VERSION 5.4 ;
NAMESCASESENSITIVE ON ;
BUSBITCHARS "[]" ;
DIVIDERCHAR "/" ;
UNITS
  DATABASE MICRONS 2000 ;
END UNITS
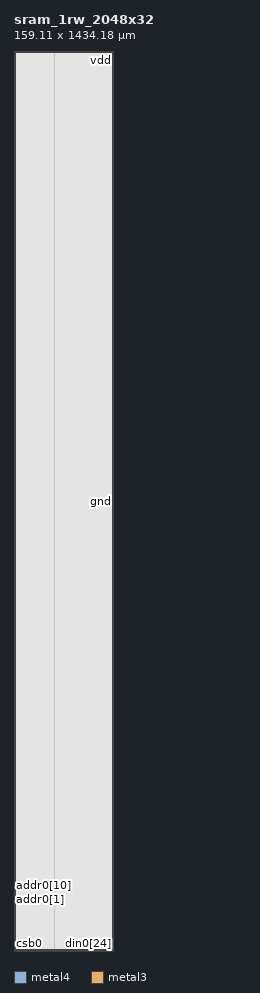
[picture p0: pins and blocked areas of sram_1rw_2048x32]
MACRO sram_1rw_2048x32
   CLASS BLOCK ;
   SIZE 159.11 BY 1434.18 ;
   SYMMETRY X Y R90 ;
   PIN din0[0]
      DIRECTION INPUT ;
      PORT
         LAYER metal4 ;
         RECT  64.725 0.0 64.865 0.14 ;
      END
   END din0[0]
   PIN din0[1]
      DIRECTION INPUT ;
      PORT
         LAYER metal4 ;
         RECT  67.585 0.0 67.725 0.14 ;
      END
   END din0[1]
   PIN din0[2]
      DIRECTION INPUT ;
      PORT
         LAYER metal4 ;
         RECT  70.445 0.0 70.585 0.14 ;
      END
   END din0[2]
   PIN din0[3]
      DIRECTION INPUT ;
      PORT
         LAYER metal4 ;
         RECT  73.305 0.0 73.445 0.14 ;
      END
   END din0[3]
   PIN din0[4]
      DIRECTION INPUT ;
      PORT
         LAYER metal4 ;
         RECT  76.165 0.0 76.305 0.14 ;
      END
   END din0[4]
   PIN din0[5]
      DIRECTION INPUT ;
      PORT
         LAYER metal4 ;
         RECT  79.025 0.0 79.165 0.14 ;
      END
   END din0[5]
   PIN din0[6]
      DIRECTION INPUT ;
      PORT
         LAYER metal4 ;
         RECT  81.885 0.0 82.025 0.14 ;
      END
   END din0[6]
   PIN din0[7]
      DIRECTION INPUT ;
      PORT
         LAYER metal4 ;
         RECT  84.745 0.0 84.885 0.14 ;
      END
   END din0[7]
   PIN din0[8]
      DIRECTION INPUT ;
      PORT
         LAYER metal4 ;
         RECT  87.605 0.0 87.745 0.14 ;
      END
   END din0[8]
   PIN din0[9]
      DIRECTION INPUT ;
      PORT
         LAYER metal4 ;
         RECT  90.465 0.0 90.605 0.14 ;
      END
   END din0[9]
   PIN din0[10]
      DIRECTION INPUT ;
      PORT
         LAYER metal4 ;
         RECT  93.325 0.0 93.465 0.14 ;
      END
   END din0[10]
   PIN din0[11]
      DIRECTION INPUT ;
      PORT
         LAYER metal4 ;
         RECT  96.185 0.0 96.325 0.14 ;
      END
   END din0[11]
   PIN din0[12]
      DIRECTION INPUT ;
      PORT
         LAYER metal4 ;
         RECT  99.045 0.0 99.185 0.14 ;
      END
   END din0[12]
   PIN din0[13]
      DIRECTION INPUT ;
      PORT
         LAYER metal4 ;
         RECT  101.905 0.0 102.045 0.14 ;
      END
   END din0[13]
   PIN din0[14]
      DIRECTION INPUT ;
      PORT
         LAYER metal4 ;
         RECT  104.765 0.0 104.905 0.14 ;
      END
   END din0[14]
   PIN din0[15]
      DIRECTION INPUT ;
      PORT
         LAYER metal4 ;
         RECT  107.625 0.0 107.765 0.14 ;
      END
   END din0[15]
   PIN din0[16]
      DIRECTION INPUT ;
      PORT
         LAYER metal4 ;
         RECT  110.485 0.0 110.625 0.14 ;
      END
   END din0[16]
   PIN din0[17]
      DIRECTION INPUT ;
      PORT
         LAYER metal4 ;
         RECT  113.345 0.0 113.485 0.14 ;
      END
   END din0[17]
   PIN din0[18]
      DIRECTION INPUT ;
      PORT
         LAYER metal4 ;
         RECT  116.205 0.0 116.345 0.14 ;
      END
   END din0[18]
   PIN din0[19]
      DIRECTION INPUT ;
      PORT
         LAYER metal4 ;
         RECT  119.065 0.0 119.205 0.14 ;
      END
   END din0[19]
   PIN din0[20]
      DIRECTION INPUT ;
      PORT
         LAYER metal4 ;
         RECT  121.925 0.0 122.065 0.14 ;
      END
   END din0[20]
   PIN din0[21]
      DIRECTION INPUT ;
      PORT
         LAYER metal4 ;
         RECT  124.785 0.0 124.925 0.14 ;
      END
   END din0[21]
   PIN din0[22]
      DIRECTION INPUT ;
      PORT
         LAYER metal4 ;
         RECT  127.645 0.0 127.785 0.14 ;
      END
   END din0[22]
   PIN din0[23]
      DIRECTION INPUT ;
      PORT
         LAYER metal4 ;
         RECT  130.505 0.0 130.645 0.14 ;
      END
   END din0[23]
   PIN din0[24]
      DIRECTION INPUT ;
      PORT
         LAYER metal4 ;
         RECT  133.365 0.0 133.505 0.14 ;
      END
   END din0[24]
   PIN din0[25]
      DIRECTION INPUT ;
      PORT
         LAYER metal4 ;
         RECT  136.225 0.0 136.365 0.14 ;
      END
   END din0[25]
   PIN din0[26]
      DIRECTION INPUT ;
      PORT
         LAYER metal4 ;
         RECT  139.085 0.0 139.225 0.14 ;
      END
   END din0[26]
   PIN din0[27]
      DIRECTION INPUT ;
      PORT
         LAYER metal4 ;
         RECT  141.945 0.0 142.085 0.14 ;
      END
   END din0[27]
   PIN din0[28]
      DIRECTION INPUT ;
      PORT
         LAYER metal4 ;
         RECT  144.805 0.0 144.945 0.14 ;
      END
   END din0[28]
   PIN din0[29]
      DIRECTION INPUT ;
      PORT
         LAYER metal4 ;
         RECT  147.665 0.0 147.805 0.14 ;
      END
   END din0[29]
   PIN din0[30]
      DIRECTION INPUT ;
      PORT
         LAYER metal4 ;
         RECT  150.525 0.0 150.665 0.14 ;
      END
   END din0[30]
   PIN din0[31]
      DIRECTION INPUT ;
      PORT
         LAYER metal4 ;
         RECT  153.385 0.0 153.525 0.14 ;
      END
   END din0[31]
   PIN addr0[0]
      DIRECTION INPUT ;
      PORT
         LAYER metal4 ;
         RECT  50.425 0.0 50.565 0.14 ;
      END
   END addr0[0]
   PIN addr0[1]
      DIRECTION INPUT ;
      PORT
         LAYER metal3 ;
         RECT  0.0 81.955 0.14 82.095 ;
      END
   END addr0[1]
   PIN addr0[2]
      DIRECTION INPUT ;
      PORT
         LAYER metal3 ;
         RECT  0.0 84.685 0.14 84.825 ;
      END
   END addr0[2]
   PIN addr0[3]
      DIRECTION INPUT ;
      PORT
         LAYER metal3 ;
         RECT  0.0 86.895 0.14 87.035 ;
      END
   END addr0[3]
   PIN addr0[4]
      DIRECTION INPUT ;
      PORT
         LAYER metal3 ;
         RECT  0.0 89.625 0.14 89.765 ;
      END
   END addr0[4]
   PIN addr0[5]
      DIRECTION INPUT ;
      PORT
         LAYER metal3 ;
         RECT  0.0 91.835 0.14 91.975 ;
      END
   END addr0[5]
   PIN addr0[6]
      DIRECTION INPUT ;
      PORT
         LAYER metal3 ;
         RECT  0.0 94.565 0.14 94.705 ;
      END
   END addr0[6]
   PIN addr0[7]
      DIRECTION INPUT ;
      PORT
         LAYER metal3 ;
         RECT  0.0 96.775 0.14 96.915 ;
      END
   END addr0[7]
   PIN addr0[8]
      DIRECTION INPUT ;
      PORT
         LAYER metal3 ;
         RECT  0.0 99.505 0.14 99.645 ;
      END
   END addr0[8]
   PIN addr0[9]
      DIRECTION INPUT ;
      PORT
         LAYER metal3 ;
         RECT  0.0 101.715 0.14 101.855 ;
      END
   END addr0[9]
   PIN addr0[10]
      DIRECTION INPUT ;
      PORT
         LAYER metal3 ;
         RECT  0.0 104.445 0.14 104.585 ;
      END
   END addr0[10]
   PIN csb0
      DIRECTION INPUT ;
      PORT
         LAYER metal3 ;
         RECT  0.0 9.935 0.14 10.075 ;
      END
   END csb0
   PIN web0
      DIRECTION INPUT ;
      PORT
         LAYER metal3 ;
         RECT  0.0 12.665 0.14 12.805 ;
      END
   END web0
   PIN clk0
      DIRECTION INPUT ;
      PORT
         LAYER metal3 ;
         RECT  0.0 10.17 0.14 10.31 ;
      END
   END clk0
   PIN wmask0[0]
      DIRECTION INPUT ;
      PORT
         LAYER metal4 ;
         RECT  53.285 0.0 53.425 0.14 ;
      END
   END wmask0[0]
   PIN wmask0[1]
      DIRECTION INPUT ;
      PORT
         LAYER metal4 ;
         RECT  56.145 0.0 56.285 0.14 ;
      END
   END wmask0[1]
   PIN wmask0[2]
      DIRECTION INPUT ;
      PORT
         LAYER metal4 ;
         RECT  59.005 0.0 59.145 0.14 ;
      END
   END wmask0[2]
   PIN wmask0[3]
      DIRECTION INPUT ;
      PORT
         LAYER metal4 ;
         RECT  61.865 0.0 62.005 0.14 ;
      END
   END wmask0[3]
   PIN dout0[0]
      DIRECTION OUTPUT ;
      PORT
         LAYER metal4 ;
         RECT  69.08 0.0 69.22 0.14 ;
      END
   END dout0[0]
   PIN dout0[1]
      DIRECTION OUTPUT ;
      PORT
         LAYER metal4 ;
         RECT  70.805 0.0 70.945 0.14 ;
      END
   END dout0[1]
   PIN dout0[2]
      DIRECTION OUTPUT ;
      PORT
         LAYER metal4 ;
         RECT  72.215 0.0 72.355 0.14 ;
      END
   END dout0[2]
   PIN dout0[3]
      DIRECTION OUTPUT ;
      PORT
         LAYER metal4 ;
         RECT  73.625 0.0 73.765 0.14 ;
      END
   END dout0[3]
   PIN dout0[4]
      DIRECTION OUTPUT ;
      PORT
         LAYER metal4 ;
         RECT  75.035 0.0 75.175 0.14 ;
      END
   END dout0[4]
   PIN dout0[5]
      DIRECTION OUTPUT ;
      PORT
         LAYER metal4 ;
         RECT  76.45 0.0 76.59 0.14 ;
      END
   END dout0[5]
   PIN dout0[6]
      DIRECTION OUTPUT ;
      PORT
         LAYER metal4 ;
         RECT  77.855 0.0 77.995 0.14 ;
      END
   END dout0[6]
   PIN dout0[7]
      DIRECTION OUTPUT ;
      PORT
         LAYER metal4 ;
         RECT  79.31 0.0 79.45 0.14 ;
      END
   END dout0[7]
   PIN dout0[8]
      DIRECTION OUTPUT ;
      PORT
         LAYER metal4 ;
         RECT  80.36 0.0 80.5 0.14 ;
      END
   END dout0[8]
   PIN dout0[9]
      DIRECTION OUTPUT ;
      PORT
         LAYER metal4 ;
         RECT  82.17 0.0 82.31 0.14 ;
      END
   END dout0[9]
   PIN dout0[10]
      DIRECTION OUTPUT ;
      PORT
         LAYER metal4 ;
         RECT  83.495 0.0 83.635 0.14 ;
      END
   END dout0[10]
   PIN dout0[11]
      DIRECTION OUTPUT ;
      PORT
         LAYER metal4 ;
         RECT  85.03 0.0 85.17 0.14 ;
      END
   END dout0[11]
   PIN dout0[12]
      DIRECTION OUTPUT ;
      PORT
         LAYER metal4 ;
         RECT  86.315 0.0 86.455 0.14 ;
      END
   END dout0[12]
   PIN dout0[13]
      DIRECTION OUTPUT ;
      PORT
         LAYER metal4 ;
         RECT  87.89 0.0 88.03 0.14 ;
      END
   END dout0[13]
   PIN dout0[14]
      DIRECTION OUTPUT ;
      PORT
         LAYER metal4 ;
         RECT  89.135 0.0 89.275 0.14 ;
      END
   END dout0[14]
   PIN dout0[15]
      DIRECTION OUTPUT ;
      PORT
         LAYER metal4 ;
         RECT  90.75 0.0 90.89 0.14 ;
      END
   END dout0[15]
   PIN dout0[16]
      DIRECTION OUTPUT ;
      PORT
         LAYER metal4 ;
         RECT  91.64 0.0 91.78 0.14 ;
      END
   END dout0[16]
   PIN dout0[17]
      DIRECTION OUTPUT ;
      PORT
         LAYER metal4 ;
         RECT  93.61 0.0 93.75 0.14 ;
      END
   END dout0[17]
   PIN dout0[18]
      DIRECTION OUTPUT ;
      PORT
         LAYER metal4 ;
         RECT  94.775 0.0 94.915 0.14 ;
      END
   END dout0[18]
   PIN dout0[19]
      DIRECTION OUTPUT ;
      PORT
         LAYER metal4 ;
         RECT  96.47 0.0 96.61 0.14 ;
      END
   END dout0[19]
   PIN dout0[20]
      DIRECTION OUTPUT ;
      PORT
         LAYER metal4 ;
         RECT  97.595 0.0 97.735 0.14 ;
      END
   END dout0[20]
   PIN dout0[21]
      DIRECTION OUTPUT ;
      PORT
         LAYER metal4 ;
         RECT  99.33 0.0 99.47 0.14 ;
      END
   END dout0[21]
   PIN dout0[22]
      DIRECTION OUTPUT ;
      PORT
         LAYER metal4 ;
         RECT  100.415 0.0 100.555 0.14 ;
      END
   END dout0[22]
   PIN dout0[23]
      DIRECTION OUTPUT ;
      PORT
         LAYER metal4 ;
         RECT  102.395 0.0 102.535 0.14 ;
      END
   END dout0[23]
   PIN dout0[24]
      DIRECTION OUTPUT ;
      PORT
         LAYER metal4 ;
         RECT  102.92 0.0 103.06 0.14 ;
      END
   END dout0[24]
   PIN dout0[25]
      DIRECTION OUTPUT ;
      PORT
         LAYER metal4 ;
         RECT  105.215 0.0 105.355 0.14 ;
      END
   END dout0[25]
   PIN dout0[26]
      DIRECTION OUTPUT ;
      PORT
         LAYER metal4 ;
         RECT  106.055 0.0 106.195 0.14 ;
      END
   END dout0[26]
   PIN dout0[27]
      DIRECTION OUTPUT ;
      PORT
         LAYER metal4 ;
         RECT  108.035 0.0 108.175 0.14 ;
      END
   END dout0[27]
   PIN dout0[28]
      DIRECTION OUTPUT ;
      PORT
         LAYER metal4 ;
         RECT  108.875 0.0 109.015 0.14 ;
      END
   END dout0[28]
   PIN dout0[29]
      DIRECTION OUTPUT ;
      PORT
         LAYER metal4 ;
         RECT  109.725 0.0 109.865 0.14 ;
      END
   END dout0[29]
   PIN dout0[30]
      DIRECTION OUTPUT ;
      PORT
         LAYER metal4 ;
         RECT  111.695 0.0 111.835 0.14 ;
      END
   END dout0[30]
   PIN dout0[31]
      DIRECTION OUTPUT ;
      PORT
         LAYER metal4 ;
         RECT  112.585 0.0 112.725 0.14 ;
      END
   END dout0[31]
   PIN vdd
      DIRECTION INOUT ;
      USE POWER ;
      SHAPE ABUTMENT ;
      PORT
         LAYER metal3 ;
         RECT  0.0 1433.48 159.11 1434.18 ;
         LAYER metal4 ;
         RECT  0.0 0.0 0.7 1434.18 ;
         LAYER metal4 ;
         RECT  158.41 0.0 159.11 1434.18 ;
         LAYER metal3 ;
         RECT  0.0 0.0 159.11 0.7 ;
      END
   END vdd
   PIN gnd
      DIRECTION INOUT ;
      USE GROUND ;
      SHAPE ABUTMENT ;
      PORT
         LAYER metal4 ;
         RECT  1.4 1.4 2.1 1432.78 ;
         LAYER metal3 ;
         RECT  1.4 1432.08 157.71 1432.78 ;
         LAYER metal3 ;
         RECT  1.4 1.4 157.71 2.1 ;
         LAYER metal4 ;
         RECT  157.01 1.4 157.71 1432.78 ;
      END
   END gnd
   OBS
   LAYER  metal1 ;
      RECT  0.14 0.14 158.97 1434.04 ;
   LAYER  metal2 ;
      RECT  0.14 0.14 158.97 1434.04 ;
   LAYER  metal3 ;
      RECT  0.28 81.815 158.97 82.235 ;
      RECT  0.14 82.235 0.28 84.545 ;
      RECT  0.14 84.965 0.28 86.755 ;
      RECT  0.14 87.175 0.28 89.485 ;
      RECT  0.14 89.905 0.28 91.695 ;
      RECT  0.14 92.115 0.28 94.425 ;
      RECT  0.14 94.845 0.28 96.635 ;
      RECT  0.14 97.055 0.28 99.365 ;
      RECT  0.14 99.785 0.28 101.575 ;
      RECT  0.14 101.995 0.28 104.305 ;
      RECT  0.14 12.945 0.28 81.815 ;
      RECT  0.14 10.45 0.28 12.525 ;
      RECT  0.14 104.725 0.28 1433.34 ;
      RECT  0.14 0.84 0.28 9.795 ;
      RECT  0.28 82.235 1.26 1431.94 ;
      RECT  0.28 1431.94 1.26 1432.92 ;
      RECT  0.28 1432.92 1.26 1433.34 ;
      RECT  1.26 82.235 157.85 1431.94 ;
      RECT  1.26 1432.92 157.85 1433.34 ;
      RECT  157.85 82.235 158.97 1431.94 ;
      RECT  157.85 1431.94 158.97 1432.92 ;
      RECT  157.85 1432.92 158.97 1433.34 ;
      RECT  0.28 0.84 1.26 1.26 ;
      RECT  0.28 1.26 1.26 2.24 ;
      RECT  0.28 2.24 1.26 81.815 ;
      RECT  1.26 0.84 157.85 1.26 ;
      RECT  1.26 2.24 157.85 81.815 ;
      RECT  157.85 0.84 158.97 1.26 ;
      RECT  157.85 1.26 158.97 2.24 ;
      RECT  157.85 2.24 158.97 81.815 ;
   LAYER  metal4 ;
      RECT  64.445 0.42 65.145 1434.04 ;
      RECT  65.145 0.14 67.305 0.42 ;
      RECT  113.765 0.14 115.925 0.42 ;
      RECT  116.625 0.14 118.785 0.42 ;
      RECT  119.485 0.14 121.645 0.42 ;
      RECT  122.345 0.14 124.505 0.42 ;
      RECT  125.205 0.14 127.365 0.42 ;
      RECT  128.065 0.14 130.225 0.42 ;
      RECT  130.925 0.14 133.085 0.42 ;
      RECT  133.785 0.14 135.945 0.42 ;
      RECT  136.645 0.14 138.805 0.42 ;
      RECT  139.505 0.14 141.665 0.42 ;
      RECT  142.365 0.14 144.525 0.42 ;
      RECT  145.225 0.14 147.385 0.42 ;
      RECT  148.085 0.14 150.245 0.42 ;
      RECT  150.945 0.14 153.105 0.42 ;
      RECT  50.845 0.14 53.005 0.42 ;
      RECT  53.705 0.14 55.865 0.42 ;
      RECT  56.565 0.14 58.725 0.42 ;
      RECT  59.425 0.14 61.585 0.42 ;
      RECT  62.285 0.14 64.445 0.42 ;
      RECT  68.005 0.14 68.8 0.42 ;
      RECT  69.5 0.14 70.165 0.42 ;
      RECT  71.225 0.14 71.935 0.42 ;
      RECT  72.635 0.14 73.025 0.42 ;
      RECT  74.045 0.14 74.755 0.42 ;
      RECT  75.455 0.14 75.885 0.42 ;
      RECT  76.87 0.14 77.575 0.42 ;
      RECT  78.275 0.14 78.745 0.42 ;
      RECT  79.73 0.14 80.08 0.42 ;
      RECT  80.78 0.14 81.605 0.42 ;
      RECT  82.59 0.14 83.215 0.42 ;
      RECT  83.915 0.14 84.465 0.42 ;
      RECT  85.45 0.14 86.035 0.42 ;
      RECT  86.735 0.14 87.325 0.42 ;
      RECT  88.31 0.14 88.855 0.42 ;
      RECT  89.555 0.14 90.185 0.42 ;
      RECT  91.17 0.14 91.36 0.42 ;
      RECT  92.06 0.14 93.045 0.42 ;
      RECT  94.03 0.14 94.495 0.42 ;
      RECT  95.195 0.14 95.905 0.42 ;
      RECT  96.89 0.14 97.315 0.42 ;
      RECT  98.015 0.14 98.765 0.42 ;
      RECT  99.75 0.14 100.135 0.42 ;
      RECT  100.835 0.14 101.625 0.42 ;
      RECT  103.34 0.14 104.485 0.42 ;
      RECT  105.635 0.14 105.775 0.42 ;
      RECT  106.475 0.14 107.345 0.42 ;
      RECT  108.455 0.14 108.595 0.42 ;
      RECT  109.295 0.14 109.445 0.42 ;
      RECT  110.145 0.14 110.205 0.42 ;
      RECT  110.905 0.14 111.415 0.42 ;
      RECT  112.115 0.14 112.305 0.42 ;
      RECT  113.005 0.14 113.065 0.42 ;
      RECT  0.98 0.14 50.145 0.42 ;
      RECT  153.805 0.14 158.13 0.42 ;
      RECT  0.98 0.42 1.12 1.12 ;
      RECT  0.98 1.12 1.12 1433.06 ;
      RECT  0.98 1433.06 1.12 1434.04 ;
      RECT  1.12 0.42 2.38 1.12 ;
      RECT  1.12 1433.06 2.38 1434.04 ;
      RECT  2.38 0.42 64.445 1.12 ;
      RECT  2.38 1.12 64.445 1433.06 ;
      RECT  2.38 1433.06 64.445 1434.04 ;
      RECT  65.145 0.42 156.73 1.12 ;
      RECT  65.145 1.12 156.73 1433.06 ;
      RECT  65.145 1433.06 156.73 1434.04 ;
      RECT  156.73 0.42 157.99 1.12 ;
      RECT  156.73 1433.06 157.99 1434.04 ;
      RECT  157.99 0.42 158.13 1.12 ;
      RECT  157.99 1.12 158.13 1433.06 ;
      RECT  157.99 1433.06 158.13 1434.04 ;
   END
END    sram_1rw_2048x32
END    LIBRARY
